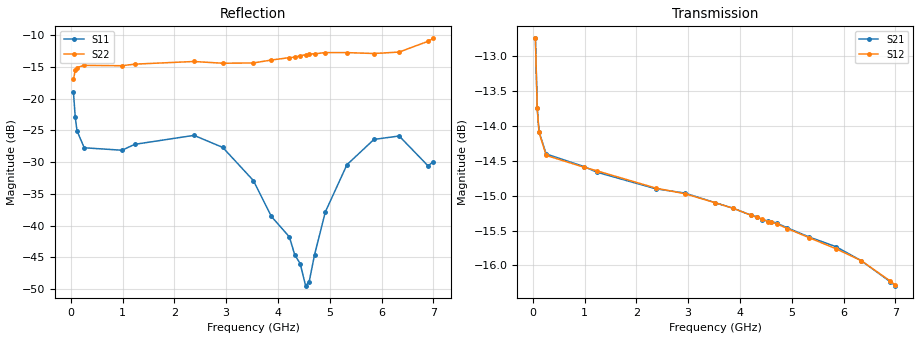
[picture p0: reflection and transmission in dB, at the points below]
! Integrated Device Technology
! Corporate Headquarters
! 6024 Silver Creek Valley Road
! San Jose, CA 95138  USA
! Phone:  1-408-284-8200
! Toll Free:  1-800-223-1366
! Webpage:  http://www.idt.com/
! Timing and RF Division
! 515 Groton Road, Suite 102
! Westford, MA 01886-6024
! Device:  F2258
! Description: Voltage Variable RF Attenuator
! Frequency:  50.0 -  6000.00 MHz
! Package:  3x3 mm Thin QFN Plastic Package: 16 pin
! Ports:  2 RF, 2 DC
!  Pin  1  = NC
!  Pin  2  = NC
!  Pin  3  = RF2  = Port 2
!  Pin  4  = GND
!  Pin  5  = Vdd
!  Pin  6  = NC
!  Pin  7  = VCTRL
!  Pin  8  = NC
!  Pin  9  = GND
!  Pin 10  = RF1  = Port 1
!  Pin 11  = NC
!  Pin 12  = NC
!  Pin 13  = NC
!  Pin 14  = NC
!  Pin 15  = NC
!  Pin 16  = NC
! Vcntrl:  1.160 Volts
! Vdd:  +3.300 Volts
! Current:  1.166 mA
! Data:  The device was measured on a the F2258 evaluation board which has
!  individual transmission lines to the RF pins.  Data was collected
!  using a calibrated network analyzer.  The evaluation board was
!  de-embedded using a TRL calibration technique.
!  The reference plane is the edge of the package pin.
! Misc:  SN 10
!  Action Tracker AT0285
! Date Measured:  2014-12-10
! Date:  2016-01-13  MJV
! Note:
!  Integrated Device Technology supplies this data as a sample of measured
!  data at the package pin for this product.  Your particular data for this
!  product may vary.
!  Data was taken at 25 degrees C.
!  Integrated Device Technology reserves the right to change this data at anytime.
!Freq_(GHz)  S11M_(dB)  S11P_(deg)  S21M_(dB)  S21P_(deg)  S12M_(dB)  S12P_(deg)  S22M_(dB)  S22P_(deg)
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# GHz S dB R 50
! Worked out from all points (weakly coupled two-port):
!   201 points, 50 MHz to 7 GHz, reference 50 ohm
!   highest |S21| = -12.74 dB at 50 MHz (marker M1); lowest = -16.3 dB at 7 GHz (marker M2)
!   lowest |S11| = -49.5 dB at 4.533 GHz (marker M3), VSWR 1.01, Z = 50.2 + j0.274 ohm
!   |S11| at or under -10 dB: start of sweep to end of sweep
!   |S22| runs from -16.9 to -10.5 dB; largest |S21 - S12| = 0.00093
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0.05  -18.93 -90.7  -12.74 -22.0  -12.74 -22.0  -16.92 -22.7
0.08475  -22.88 -73.7  -13.74 -15.7  -13.74 -15.7  -15.50 -12.4
0.1195  -25.07 -60.5  -14.08 -12.6  -14.09 -12.6  -15.07 -10.2
0.2585  -27.73 -33.0  -14.40 -9.5  -14.42 -9.5  -14.72 -10.3
0.98825  -28.12 -18.8  -14.58 -17.2  -14.59 -17.2  -14.78 -29.1
1.2315  -27.19 -16.0  -14.66 -20.7  -14.64 -20.7  -14.53 -35.2
2.37825  -25.77 -3.5  -14.90 -37.4  -14.89 -37.4  -14.11 -62.9
2.93425  -27.68 6.4  -14.96 -45.7  -14.97 -45.7  -14.39 -79.2
3.525  -32.91 23.2  -15.10 -54.7  -15.10 -54.7  -14.34 -101.2
3.8725  -38.57 43.3  -15.18 -60.0  -15.18 -60.0  -13.88 -114.1
4.22  -41.80 71.0  -15.28 -65.2  -15.28 -65.2  -13.50 -124.3
4.32425  -44.66 67.0  -15.30 -66.7  -15.31 -66.7  -13.43 -126.8
4.4285  -46.01 63.3  -15.34 -68.3  -15.33 -68.3  -13.22 -129.4
4.53275  -49.50 54.6  -15.36 -69.8  -15.37 -69.8  -13.04 -131.5
4.60225  -48.87 34.6  -15.37 -70.8  -15.38 -70.7  -12.93 -132.9
4.7065  -44.60 -6.2  -15.39 -72.3  -15.40 -72.3  -12.90 -134.7
4.915  -37.84 -24.8  -15.46 -75.3  -15.47 -75.3  -12.71 -137.6
5.332  -30.40 -21.8  -15.59 -81.2  -15.60 -81.2  -12.71 -143.4
5.85325  -26.41 -11.2  -15.73 -88.6  -15.76 -88.6  -12.85 -152.7
6.33975  -25.87 3.4  -15.93 -95.6  -15.93 -95.6  -12.62 -165.0
6.89575  -30.57 67.2  -16.23 -102.8  -16.22 -102.9  -10.93 179.2
7  -29.96 92.3  -16.29 -104.0  -16.28 -104.1  -10.46 176.6
